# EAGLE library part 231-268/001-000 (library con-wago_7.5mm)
Serie 231, Stiftleiste mit geraden Einlötstiften / Series 231, Male connector with straight solder pins Polzahl / Pole No.: 8 Rastermaß / Pitch: 7.5 mm Bemessungsspannung / Rated Voltage: 630 V Nennstrom / Nominal Current: 16 A Lötstiftlänge: / Solder Pin Length: 5 mm Farbe / Color: grau / gray Stand: 01.01.2012. Die jeweils aktuellen Daten zu diesem Artikel finden Sie in unserem Produktkatalog, den Sie unter www.wago.com einsehen können. As of: 01/01/2012. Please find the newest data for this article in our product catalogue, which can be viewed under www.wago.com.

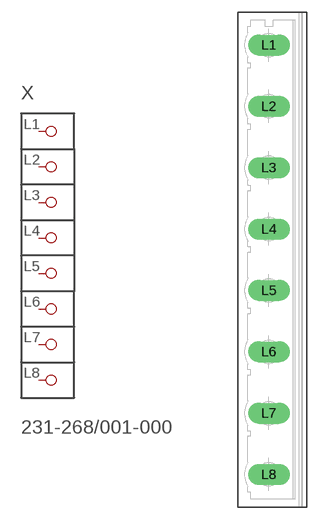
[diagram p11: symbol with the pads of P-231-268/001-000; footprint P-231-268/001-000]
Designator prefix X

## 231-268/001-000  [P-231-268/001-000]
L1  P1
L2  P2
L3  P3
L4  P4
L5  P5
L6  P6
L7  P7
L8  P8

## Footprint P-231-268/001-000 (pad centres in mm)
drill 1.7 long: L1 -0.4,26.25; L2 -0.4,18.75; L3 -0.4,11.25; L4 -0.4,3.75; L5 -0.4,-3.75; L6 -0.4,-11.25; L7 -0.4,-18.75; L8 -0.4,-26.25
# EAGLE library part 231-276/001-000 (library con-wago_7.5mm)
Serie 231, Stiftleiste mit geraden Einlötstiften / Series 231, Male connector with straight solder pins Polzahl / Pole No.: 16 Rastermaß / Pitch: 7.5 mm Bemessungsspannung / Rated Voltage: 630 V Nennstrom / Nominal Current: 16 A Lötstiftlänge: / Solder Pin Length: 5 mm Farbe / Color: grau / gray Stand: 01.01.2012. Die jeweils aktuellen Daten zu diesem Artikel finden Sie in unserem Produktkatalog, den Sie unter www.wago.com einsehen können. As of: 01/01/2012. Please find the newest data for this article in our product catalogue, which can be viewed under www.wago.com.

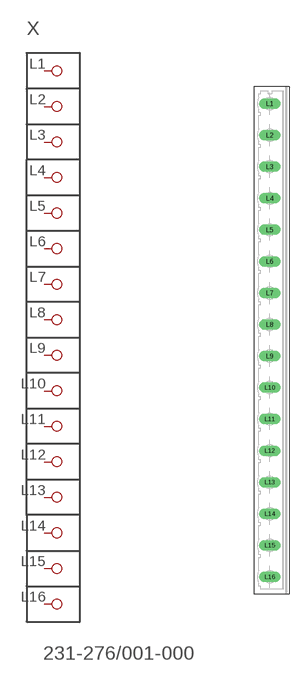
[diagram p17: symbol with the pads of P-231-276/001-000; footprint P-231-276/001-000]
Designator prefix X

## 231-276/001-000  [P-231-276/001-000]
L1  P1
L2  P2
L3  P3
L4  P4
L5  P5
L6  P6
L7  P7
L8  P8
L9  P9
L10  P10
L11  P11
L12  P12
L13  P13
L14  P14
L15  P15
L16  P16

## Footprint P-231-276/001-000 (pad centres in mm)
drill 1.7 long: L1 -0.4,56.25; L2 -0.4,48.75; L3 -0.4,41.25; L4 -0.4,33.75; L5 -0.4,26.25; L6 -0.4,18.75; L7 -0.4,11.25; L8 -0.4,3.75; L9 -0.4,-3.75; L10 -0.4,-11.25; L11 -0.4,-18.75; L12 -0.4,-26.25; L13 -0.4,-33.75; L14 -0.4,-41.25; L15 -0.4,-48.75; L16 -0.4,-56.25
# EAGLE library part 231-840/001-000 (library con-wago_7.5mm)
Serie 231, Stiftleiste mit abgewinkelten Einlötstiften / Series 231, Male connector with angled solder pins Polzahl / Pole No.: 10 Rastermaß / Pitch: 7.5 mm Bemessungsspannung / Rated Voltage: 630 V Nennstrom / Nominal Current: 12 A Lötstiftlänge: / Solder Pin Length: 3.8 mm Farbe / Color: grau / gray Stand: 01.01.2012. Die jeweils aktuellen Daten zu diesem Artikel finden Sie in unserem Produktkatalog, den Sie unter www.wago.com einsehen können. As of: 01/01/2012. Please find the newest data for this article in our product catalogue, which can be viewed under www.wago.com.

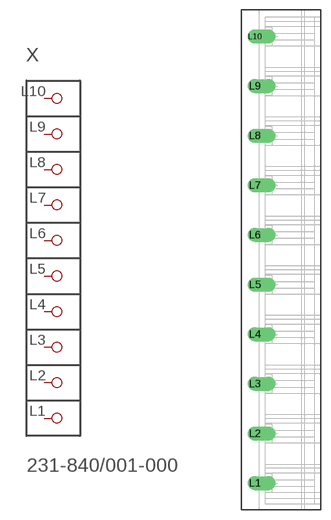
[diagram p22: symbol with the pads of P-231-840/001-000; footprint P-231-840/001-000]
Designator prefix X

## 231-840/001-000  [P-231-840/001-000]
L1  P1
L2  P2
L3  P3
L4  P4
L5  P5
L6  P6
L7  P7
L8  P8
L9  P9
L10  P10

## Footprint P-231-840/001-000 (pad centres in mm)
drill 1.4 offset: L1 -4,-33.75; L2 -4,-26.25; L3 -4,-18.75; L4 -4,-11.25; L5 -4,-3.75; L6 -4,3.75; L7 -4,11.25; L8 -4,18.75; L9 -4,26.25; L10 -4,33.75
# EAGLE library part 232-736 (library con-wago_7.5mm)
Serie 232, Federleiste mit geraden Einlötstiften / Series 232, Female connector with straight solder pins Polzahl / Pole No.: 6 Rastermaß / Pitch: 7.5 mm Bemessungsspannung / Rated Voltage: 630 V Nennstrom / Nominal Current: 12 A Lötstiftlänge: / Solder Pin Length: 5 mm Farbe / Color: grau / gray Stand: 01.01.2012. Die jeweils aktuellen Daten zu diesem Artikel finden Sie in unserem Produktkatalog, den Sie unter www.wago.com einsehen können. As of: 01/01/2012. Please find the newest data for this article in our product catalogue, which can be viewed under www.wago.com.

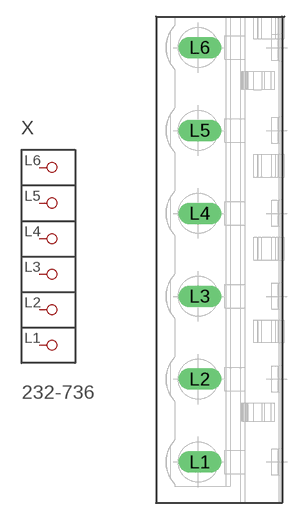
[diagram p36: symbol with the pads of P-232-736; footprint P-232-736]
Designator prefix X

## 232-736  [P-232-736]
L1  P1
L2  P2
L3  P3
L4  P4
L5  P5
L6  P6

## Footprint P-232-736 (pad centres in mm)
drill 1.3 long: L1 -1.983,-18.3; L2 -1.983,-10.8; L3 -1.983,-3.3; L4 -1.983,4.2; L5 -1.983,11.7; L6 -1.983,19.2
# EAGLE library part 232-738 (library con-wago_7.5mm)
Serie 232, Federleiste mit geraden Einlötstiften / Series 232, Female connector with straight solder pins Polzahl / Pole No.: 8 Rastermaß / Pitch: 7.5 mm Bemessungsspannung / Rated Voltage: 630 V Nennstrom / Nominal Current: 12 A Lötstiftlänge: / Solder Pin Length: 5 mm Farbe / Color: grau / gray Stand: 01.01.2012. Die jeweils aktuellen Daten zu diesem Artikel finden Sie in unserem Produktkatalog, den Sie unter www.wago.com einsehen können. As of: 01/01/2012. Please find the newest data for this article in our product catalogue, which can be viewed under www.wago.com.

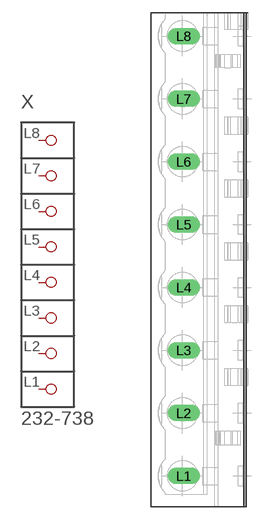
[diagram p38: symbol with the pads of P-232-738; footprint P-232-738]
Designator prefix X

## 232-738  [P-232-738]
L1  P1
L2  P2
L3  P3
L4  P4
L5  P5
L6  P6
L7  P7
L8  P8

## Footprint P-232-738 (pad centres in mm)
drill 1.3 long: L1 -2.056,-25.8; L2 -2.056,-18.3; L3 -2.056,-10.8; L4 -2.056,-3.3; L5 -2.056,4.2; L6 -2.056,11.7; L7 -2.056,19.2; L8 -2.056,26.7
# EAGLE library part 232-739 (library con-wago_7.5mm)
Serie 232, Federleiste mit geraden Einlötstiften / Series 232, Female connector with straight solder pins Polzahl / Pole No.: 9 Rastermaß / Pitch: 7.5 mm Bemessungsspannung / Rated Voltage: 630 V Nennstrom / Nominal Current: 12 A Lötstiftlänge: / Solder Pin Length: 5 mm Farbe / Color: grau / gray Stand: 01.01.2012. Die jeweils aktuellen Daten zu diesem Artikel finden Sie in unserem Produktkatalog, den Sie unter www.wago.com einsehen können. As of: 01/01/2012. Please find the newest data for this article in our product catalogue, which can be viewed under www.wago.com.

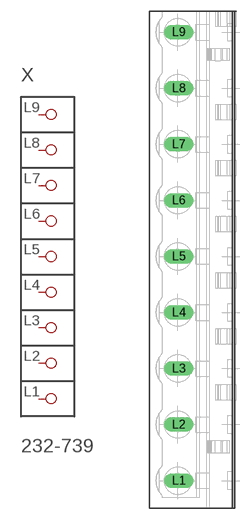
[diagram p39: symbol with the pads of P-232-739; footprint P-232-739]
Designator prefix X

## 232-739  [P-232-739]
L1  P1
L2  P2
L3  P3
L4  P4
L5  P5
L6  P6
L7  P7
L8  P8
L9  P9

## Footprint P-232-739 (pad centres in mm)
drill 1.3 long: L1 -2.092,-29.55; L2 -2.092,-22.05; L3 -2.092,-14.55; L4 -2.092,-7.05; L5 -2.092,0.45; L6 -2.092,7.95; L7 -2.092,15.45; L8 -2.092,22.95; L9 -2.092,30.45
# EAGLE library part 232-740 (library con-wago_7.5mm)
Serie 232, Federleiste mit geraden Einlötstiften / Series 232, Female connector with straight solder pins Polzahl / Pole No.: 10 Rastermaß / Pitch: 7.5 mm Bemessungsspannung / Rated Voltage: 630 V Nennstrom / Nominal Current: 12 A Lötstiftlänge: / Solder Pin Length: 5 mm Farbe / Color: grau / gray Stand: 01.01.2012. Die jeweils aktuellen Daten zu diesem Artikel finden Sie in unserem Produktkatalog, den Sie unter www.wago.com einsehen können. As of: 01/01/2012. Please find the newest data for this article in our product catalogue, which can be viewed under www.wago.com.

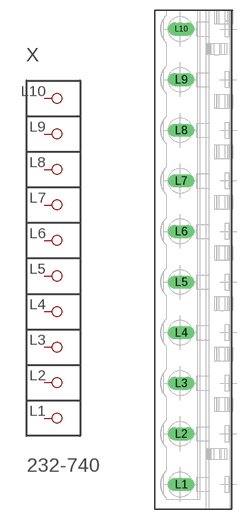
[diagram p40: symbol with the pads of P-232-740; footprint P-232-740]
Designator prefix X

## 232-740  [P-232-740]
L1  P1
L2  P2
L3  P3
L4  P4
L5  P5
L6  P6
L7  P7
L8  P8
L9  P9
L10  P10

## Footprint P-232-740 (pad centres in mm)
drill 1.3 long: L1 -2.129,-33.3; L2 -2.129,-25.8; L3 -2.129,-18.3; L4 -2.129,-10.8; L5 -2.129,-3.3; L6 -2.129,4.2; L7 -2.129,11.7; L8 -2.129,19.2; L9 -2.129,26.7; L10 -2.129,34.2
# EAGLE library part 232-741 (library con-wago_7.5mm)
Serie 232, Federleiste mit geraden Einlötstiften / Series 232, Female connector with straight solder pins Polzahl / Pole No.: 11 Rastermaß / Pitch: 7.5 mm Bemessungsspannung / Rated Voltage: 630 V Nennstrom / Nominal Current: 12 A Lötstiftlänge: / Solder Pin Length: 5 mm Farbe / Color: grau / gray Stand: 01.01.2012. Die jeweils aktuellen Daten zu diesem Artikel finden Sie in unserem Produktkatalog, den Sie unter www.wago.com einsehen können. As of: 01/01/2012. Please find the newest data for this article in our product catalogue, which can be viewed under www.wago.com.

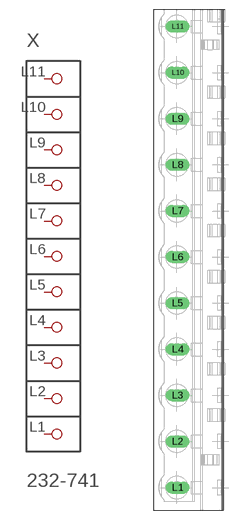
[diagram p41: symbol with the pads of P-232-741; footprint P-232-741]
Designator prefix X

## 232-741  [P-232-741]
L1  P1
L2  P2
L3  P3
L4  P4
L5  P5
L6  P6
L7  P7
L8  P8
L9  P9
L10  P10
L11  P11

## Footprint P-232-741 (pad centres in mm)
drill 1.3 long: L1 -2.166,-37.05; L2 -2.166,-29.55; L3 -2.166,-22.05; L4 -2.166,-14.55; L5 -2.166,-7.05; L6 -2.166,0.45; L7 -2.166,7.95; L8 -2.166,15.45; L9 -2.166,22.95; L10 -2.166,30.45; L11 -2.166,37.95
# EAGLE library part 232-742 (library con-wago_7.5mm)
Serie 232, Federleiste mit geraden Einlötstiften / Series 232, Female connector with straight solder pins Polzahl / Pole No.: 12 Rastermaß / Pitch: 7.5 mm Bemessungsspannung / Rated Voltage: 630 V Nennstrom / Nominal Current: 12 A Lötstiftlänge: / Solder Pin Length: 5 mm Farbe / Color: grau / gray Stand: 01.01.2012. Die jeweils aktuellen Daten zu diesem Artikel finden Sie in unserem Produktkatalog, den Sie unter www.wago.com einsehen können. As of: 01/01/2012. Please find the newest data for this article in our product catalogue, which can be viewed under www.wago.com.

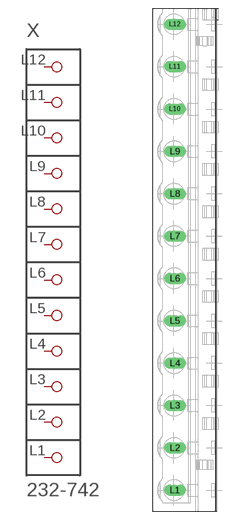
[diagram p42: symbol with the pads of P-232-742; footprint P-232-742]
Designator prefix X

## 232-742  [P-232-742]
L1  P1
L2  P2
L3  P3
L4  P4
L5  P5
L6  P6
L7  P7
L8  P8
L9  P9
L10  P10
L11  P11
L12  P12

## Footprint P-232-742 (pad centres in mm)
drill 1.3 long: L1 -2.204,-40.8; L2 -2.204,-33.3; L3 -2.204,-25.8; L4 -2.204,-18.3; L5 -2.204,-10.8; L6 -2.204,-3.3; L7 -2.204,4.2; L8 -2.204,11.7; L9 -2.204,19.2; L10 -2.204,26.7; L11 -2.204,34.2; L12 -2.204,41.7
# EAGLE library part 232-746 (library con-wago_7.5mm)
Serie 232, Federleiste mit geraden Einlötstiften / Series 232, Female connector with straight solder pins Polzahl / Pole No.: 16 Rastermaß / Pitch: 7.5 mm Bemessungsspannung / Rated Voltage: 630 V Nennstrom / Nominal Current: 12 A Lötstiftlänge: / Solder Pin Length: 5 mm Farbe / Color: grau / gray Stand: 01.01.2012. Die jeweils aktuellen Daten zu diesem Artikel finden Sie in unserem Produktkatalog, den Sie unter www.wago.com einsehen können. As of: 01/01/2012. Please find the newest data for this article in our product catalogue, which can be viewed under www.wago.com.

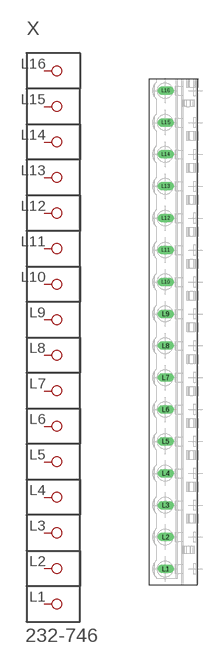
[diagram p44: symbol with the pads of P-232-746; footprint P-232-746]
Designator prefix X

## 232-746  [P-232-746]
L1  P1
L2  P2
L3  P3
L4  P4
L5  P5
L6  P6
L7  P7
L8  P8
L9  P9
L10  P10
L11  P11
L12  P12
L13  P13
L14  P14
L15  P15
L16  P16

## Footprint P-232-746 (pad centres in mm)
drill 1.3 long: L1 -2.352,-55.902; L2 -2.352,-48.402; L3 -2.352,-40.902; L4 -2.352,-33.402; L5 -2.352,-25.902; L6 -2.352,-18.402; L7 -2.352,-10.902; L8 -2.352,-3.402; L9 -2.352,4.098; L10 -2.352,11.598; L11 -2.352,19.098; L12 -2.352,26.598; L13 -2.352,34.098; L14 -2.352,41.598; L15 -2.352,49.098; L16 -2.352,56.598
